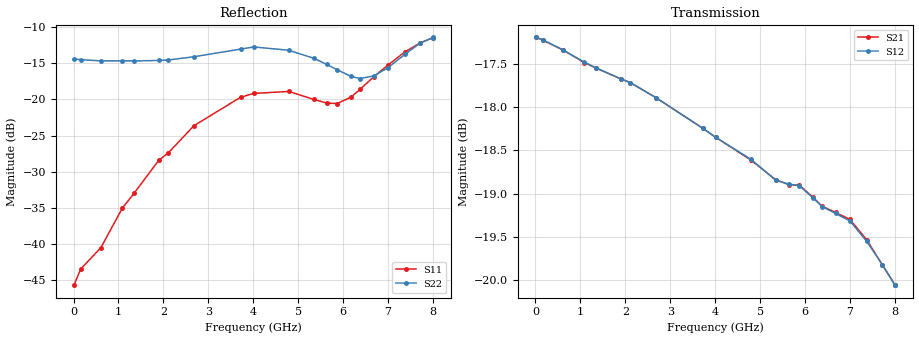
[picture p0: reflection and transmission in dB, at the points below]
! DEVICE ID: PE43712
! File Path: z:\PE43713\PE43713_CHAR_NOM_04292014\AMB\3p300\LS_ATT_16p00dB\PE43713_AMB_3p300V_3p000V_0p000V_LS_ATT_16p00dB_S2P_SN_10_A0139A.s2p
! Serial: 10
! Lot: A0139A
! Temp: 25C
! VDD: 3.300
! VSS: 0.000
! Control_Hi: 3.000
! Control_Lo: 0.000
! Attenuation Step: 16.00dB
! Port 1: RF1
! Port 2: RF2
! ThroughPath:1-2
! IDD: 0.0001461276
! ISS: -1.046e-007
#  Hz  S  RI  R  50
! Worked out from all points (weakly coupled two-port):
!   801 points, 10 MHz to 8.01 GHz, reference 50 ohm
!   highest |S21| = -17.20 dB at 10 MHz (marker M1); lowest = -20.0 dB at 8 GHz (marker M2)
!   lowest |S11| = -45.7 dB at 10 MHz (marker M3), VSWR 1.01, Z = 50.5 + j0.0442 ohm
!   |S11| at or under -10 dB: start of sweep to end of sweep
!   |S22| runs from -17.2 to -11.5 dB; largest |S21 - S12| = 0.0005
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1e7  0.0052 0.000438  0.1381 -0.000678  0.1381 -0.000671  -0.1896 0.0012
1.6e8  0.0063 0.00238  0.1373 -0.00898  0.1374 -0.00897  -0.1873 0.0118
6.1e8  0.00583 0.00747  0.132 -0.032  0.132 -0.032  -0.18 0.0383
1.09e9  0.00494 0.0171  0.1223 -0.0536  0.1224 -0.0536  -0.1716 0.0669
1.35e9  0.00595 0.0217  0.1161 -0.064  0.1161 -0.0641  -0.1654 0.0803
1.9e9  0.0116 0.0362  0.1002 -0.0839  0.1002 -0.0839  -0.1467 0.1134
2.11e9  0.0141 0.0403  0.0933 -0.0906  0.0933 -0.0906  -0.1402 0.1234
2.68e9  0.0256 0.0605  0.072 -0.1052  0.072 -0.1052  -0.1137 0.1603
3.72e9  0.0321 0.0982  0.0287 -0.119  0.0287 -0.119  -0.0857 0.2048
4.01e9  0.0321 0.1049  0.0166 -0.1198  0.0166 -0.1198  -0.0839 0.2138
4.79e9  0.0327 0.1084  -0.0142 -0.1165  -0.0143 -0.1166  -0.068 0.207
5.35e9  0.0437 0.0897  -0.0341 -0.1091  -0.0341 -0.109  -0.0502 0.185
5.64e9  0.0538 0.0772  -0.0435 -0.1049  -0.0435 -0.105  -0.0304 0.1711
5.87e9  0.0635 0.0686  -0.052 -0.1009  -0.0518 -0.1009  -0.0106 0.1595
6.17e9  0.0821 0.0625  -0.0619 -0.093  -0.0616 -0.0931  0.0205 0.1426
6.38e9  0.0998 0.0615  -0.067 -0.0877  -0.0669 -0.0877  0.0455 0.1313
6.68e9  0.1296 0.0599  -0.0749 -0.0798  -0.0747 -0.0798  0.0835 0.1184
7e9  0.1603 0.0632  -0.0829 -0.0699  -0.0827 -0.0698  0.1196 0.114
7.37e9  0.1995 0.0707  -0.0893 -0.0563  -0.0891 -0.0562  0.1653 0.1191
7.72e9  0.2321 0.0794  -0.0921 -0.0441  -0.092 -0.0443  0.2078 0.1292
8e9  0.2501 0.0893  -0.093 -0.0352  -0.0929 -0.0353  0.2299 0.1352
8.01e9  0.2507 0.09  -0.0931 -0.035  -0.093 -0.0352  0.2306 0.1353
